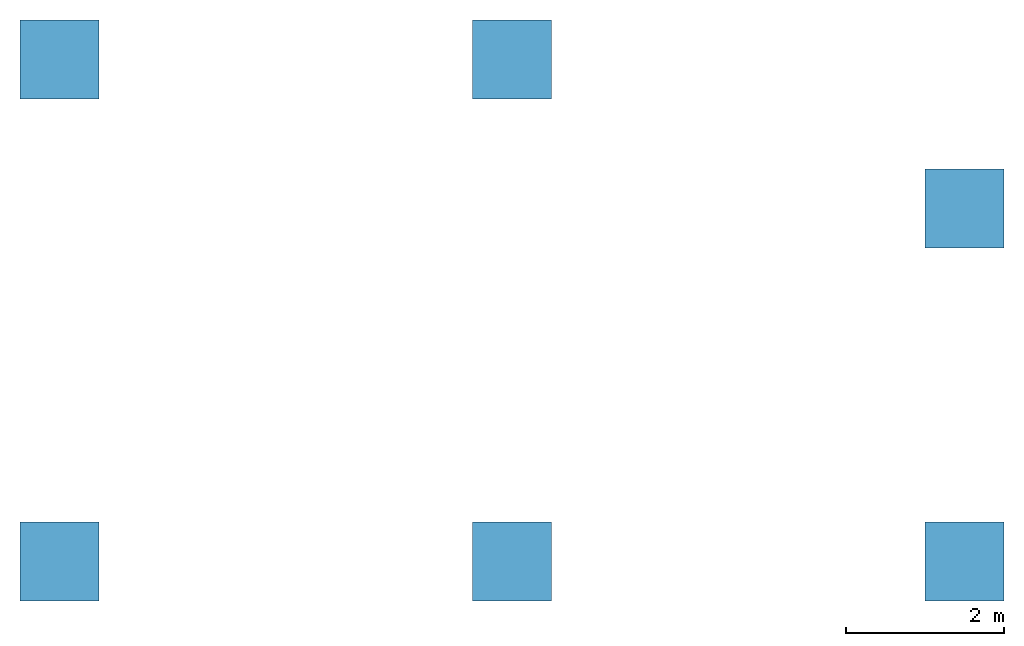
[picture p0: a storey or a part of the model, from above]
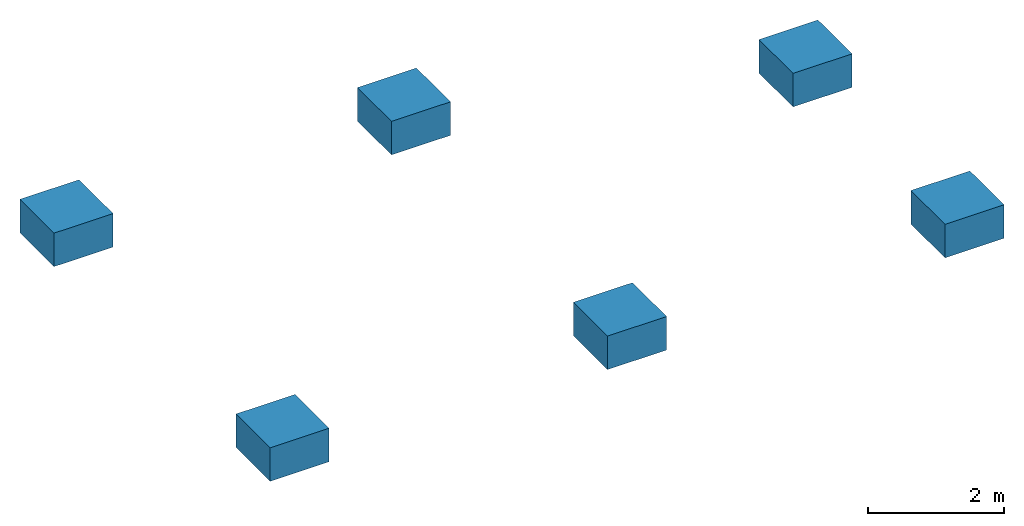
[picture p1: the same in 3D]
Properties of the parts of a building model (IFC2X3)

# File
Description: ViewDefinition [CoordinationView_V2.0], Option [Drawing Scale: 100.000000], Option [Global Unique Identifiers (GUID): Keep existing], Option [Elements to export: Visible elements (on all stories)], Option [Partial Structure Display: Entire Model], Option [IFC Domain: All], Option [Structural Function: All Elements], Option [Convert Grid elements: On], Option [Convert IFC Annotations and ARCHICAD 2D elements: Off], Option [Convert 2D symbols of Doors and Windows: Off], Option [Explode Composite and Complex Profile elements into parts: Off], Option [Export geometries that Participates in Collision Detection only: Off], Option [Multi-skin complex geometries: Building element parts], Option [Elements in Solid Element Operations: Extruded/revolved], Option [Elements with junctions: Extruded/revolved without junctions], Option [Slabs with slanted edge(s): Extruded], Option [Use legacy geometric methods as in Coordination View 1.0: Off], Option [IFC Site Geometry: As boundary representation (BRep)], Option [IFC Site Location: At Project Origin], Option [Curtain Wall export mode: Container Element], Option [Railing export mode: Single Element], Option [Stair export mode: Container Element], Option [Properties To Export: All properties], Option [Space containment: Off], Option [Bounding Box: Off], Option [Geometry to type objects: Off], Option [Element Properties: Off], Option [Property Type Element Parameter: Off], Option [Quantity Type Element Parameter: Off], Option [IFC Base Quantities: Off], Option [Window Door Lining and Panel Parameters: On], Option [IFC Space boundaries: Off], Option [ARCHICAD Zone Categories as IFC Space classification data: Off], Option [Element Classifications: Off]
File name: E:\(2)_Prepa_cours\Archicad\(4) Chapitre 2\(3) Maison Dom-Ino\(5a) MAison-Dom-Ino.ifc
Time: 2018-02-27T09:42:08
Author: Nom de famille Prénom
Organization: (Atelier d'architecture.... )
Written by: The EXPRESS Data Manager Version 5.02.0100.09 : 26 Sep 2013
Made in: IFC file generated by GRAPHISOFT ARCHICAD-64 21.0.0 FRA FULL Windows version (IFC add-on version: 4022 FRA FULL).
Authorization: Nom de famille Prénom

# IfcProject, (Construction de... )
Phase: (provisoire, définitif...)

# IfcSite, Site
RefLatitude: 48, 52, 0, 0; RefLongitude: 2, 20, 0, 0; RefElevation: 26 m

# IfcBuildingStorey (4)
In: Bâtiment
Name | Elevation (m)
FF | -0.85
RdC | 0
R+1 | 2.7
TT | 5.4

# IfcBuildingElementProxy: IfcBuildingElementProxy (6)
Material: GENERIQUE - STRUCTURE
AC_Pset_RenovationAndPhasing - Renovation Status: Existing
Name | In
VOLEE-001 | RdC
PALIER-001 | RdC
VOLEE-002 | RdC
VOLEE-001 | R+1
PALIER-001 | R+1
VOLEE-002 | R+1

# IfcBuildingElementProxy: Type d'escalier (2)
AC_Pset_RenovationAndPhasing - Renovation Status: Existing
Name | In
ESC-001 | RdC
ESC-001 | R+1

# IfcColumn: GENERIQUE - STRUCTURE 350 x 350 (14)
Material: GENERIQUE - STRUCTURE
AC_Pset_RenovationAndPhasing - Renovation Status: Existing
Pset_ColumnCommon - LoadBearing: yes; Reference: GENERIQUE - STRUCTURE 350 x 350
Name | In
8 x PotB-001 | RdC
6 x PotB-001 | R+1

# IfcSlab: GENERIQUE - STRUCTURE 250 (3)
Type - PredefinedType: FLOOR
Material: GENERIQUE - STRUCTURE 0.25 m
AC_Pset_RenovationAndPhasing - Renovation Status: Existing
Pset_SlabCommon - LoadBearing: yes; IsExternal: no
Name | In
DC_BA_Isol-002 | RdC
DC_BA_Isol-002 | R+1
DC_BA_Isol-002 | TT

# IfcWall: Semelle isolée 1000 x 600 (6)
In: FF
Material: GENERIQUE - STRUCTURE
AC_Pset_RenovationAndPhasing - Renovation Status: Existing
Pset_WallCommon - LoadBearing: yes; IsExternal: yes
